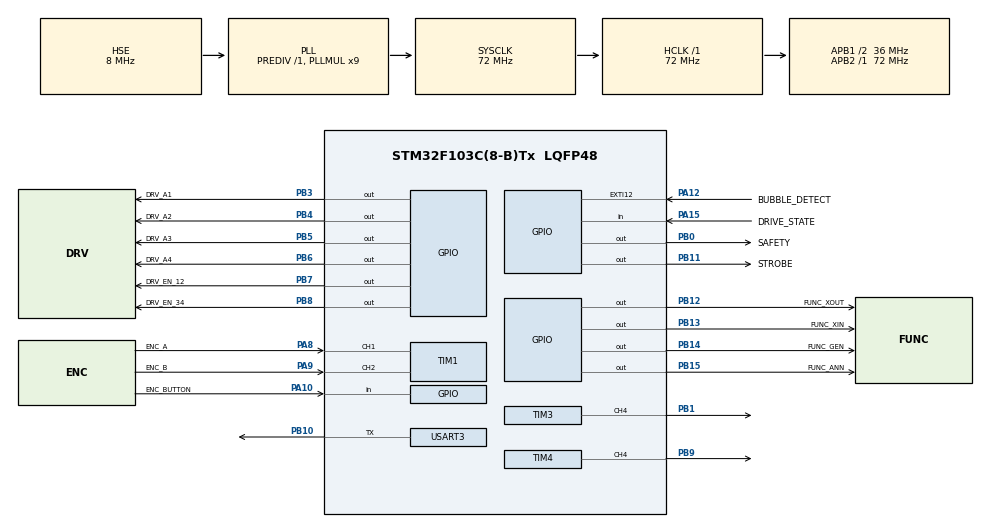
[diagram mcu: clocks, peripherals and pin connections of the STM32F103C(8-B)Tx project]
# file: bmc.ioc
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Dma.Request0=TIM2_UP
Dma.Request1=TIM2_CH1
Dma.Request2=TIM2_CH2/CH4
Dma.TIM2_CH1.1.Direction=DMA_MEMORY_TO_PERIPH
Dma.TIM2_CH1.1.Instance=DMA1_Channel5
Dma.TIM2_CH1.1.MemDataAlignment=DMA_MDATAALIGN_HALFWORD
Dma.TIM2_CH1.1.MemInc=DMA_MINC_DISABLE
Dma.TIM2_CH1.1.Mode=DMA_CIRCULAR
Dma.TIM2_CH1.1.PeriphDataAlignment=DMA_PDATAALIGN_HALFWORD
Dma.TIM2_CH1.1.PeriphInc=DMA_PINC_DISABLE
Dma.TIM2_CH1.1.Priority=DMA_PRIORITY_VERY_HIGH
Dma.TIM2_CH2/CH4.2.Direction=DMA_MEMORY_TO_PERIPH
Dma.TIM2_CH2/CH4.2.Instance=DMA1_Channel7
Dma.TIM2_CH2/CH4.2.MemDataAlignment=DMA_MDATAALIGN_HALFWORD
Dma.TIM2_CH2/CH4.2.MemInc=DMA_MINC_DISABLE
Dma.TIM2_CH2/CH4.2.Mode=DMA_CIRCULAR
Dma.TIM2_CH2/CH4.2.PeriphDataAlignment=DMA_PDATAALIGN_HALFWORD
Dma.TIM2_CH2/CH4.2.PeriphInc=DMA_PINC_DISABLE
Dma.TIM2_CH2/CH4.2.Priority=DMA_PRIORITY_VERY_HIGH
Dma.TIM2_UP.0.Direction=DMA_MEMORY_TO_PERIPH
Dma.TIM2_UP.0.Instance=DMA1_Channel2
Dma.TIM2_UP.0.MemDataAlignment=DMA_MDATAALIGN_HALFWORD
Dma.TIM2_UP.0.MemInc=DMA_MINC_DISABLE
Dma.TIM2_UP.0.Mode=DMA_CIRCULAR
Dma.TIM2_UP.0.PeriphDataAlignment=DMA_PDATAALIGN_HALFWORD
Dma.TIM2_UP.0.PeriphInc=DMA_PINC_DISABLE
Dma.TIM2_UP.0.Priority=DMA_PRIORITY_VERY_HIGH
Mcu.Family=STM32F1
Mcu.Name=STM32F103C(8-B)Tx
Mcu.Package=LQFP48
NVIC.DMA1_Channel2_IRQn=true\:0\:0\:false\:false\:true\:false\:true
NVIC.DMA1_Channel5_IRQn=true\:0\:0\:false\:false\:true\:false\:true
NVIC.DMA1_Channel7_IRQn=true\:0\:0\:false\:false\:true\:false\:true
NVIC.PriorityGroup=NVIC_PRIORITYGROUP_4
PA10.GPIO_Label=ENC_BUTTON
PA10.GPIO_PuPd=GPIO_PULLUP
PA10.Signal=GPIO_Input
PA12.GPIO_Label=BUBBLE_DETECT
PA12.Signal=GPXTI12
PA15.GPIO_Label=DRIVE_STATE
PA15.GPIO_PuPd=GPIO_PULLUP
PA15.Signal=GPIO_Input
PA8.GPIO_Label=ENC_A
PA8.GPIO_PuPd=GPIO_PULLUP
PA8.Signal=S_TIM1_CH1
PA9.GPIO_Label=ENC_B
PA9.GPIO_PuPd=GPIO_PULLUP
PA9.Signal=S_TIM1_CH2
PB0.GPIO_Label=SAFETY
PB0.GPIO_PuPd=GPIO_PULLUP
PB0.GPIO_Speed=GPIO_SPEED_FREQ_HIGH
PB0.PinState=GPIO_PIN_SET
PB0.Signal=GPIO_Output
PB1.Signal=S_TIM3_CH4
PB10.Mode=Half_duplex(single_wire_mode)
PB10.Signal=USART3_TX
PB11.GPIO_Label=STROBE
PB11.GPIO_Speed=GPIO_SPEED_FREQ_HIGH
PB11.Signal=GPIO_Output
PB12.GPIO_Label=FUNC_XOUT
PB12.GPIO_Speed=GPIO_SPEED_FREQ_HIGH
PB12.Signal=GPIO_Output
PB13.GPIO_Label=FUNC_XIN
PB13.GPIO_Speed=GPIO_SPEED_FREQ_HIGH
PB13.Signal=GPIO_Output
PB14.GPIO_Label=FUNC_GEN
PB14.GPIO_Speed=GPIO_SPEED_FREQ_HIGH
PB14.Signal=GPIO_Output
PB15.GPIO_Label=FUNC_ANN
PB15.GPIO_Speed=GPIO_SPEED_FREQ_HIGH
PB15.Signal=GPIO_Output
PB3.GPIO_Label=DRV_A1
PB3.GPIO_Speed=GPIO_SPEED_FREQ_HIGH
PB3.Signal=GPIO_Output
PB4.GPIO_Label=DRV_A2
PB4.GPIO_Speed=GPIO_SPEED_FREQ_HIGH
PB4.Signal=GPIO_Output
PB5.GPIO_Label=DRV_A3
PB5.GPIO_Speed=GPIO_SPEED_FREQ_HIGH
PB5.Signal=GPIO_Output
PB6.GPIO_Label=DRV_A4
PB6.GPIO_Speed=GPIO_SPEED_FREQ_HIGH
PB6.Signal=GPIO_Output
PB7.GPIO_Label=DRV_EN_12
PB7.GPIO_Speed=GPIO_SPEED_FREQ_HIGH
PB7.Signal=GPIO_Output
PB8.GPIO_Label=DRV_EN_34
PB8.GPIO_PuPd=GPIO_NOPULL
PB8.GPIO_Speed=GPIO_SPEED_FREQ_HIGH
PB8.PinState=GPIO_PIN_RESET
PB8.Signal=GPIO_Output
PB9.Signal=S_TIM4_CH4
PD0-OSC_IN.Mode=HSE-External-Oscillator
PD0-OSC_IN.Signal=RCC_OSC_IN
PD1-OSC_OUT.Mode=HSE-External-Oscillator
PD1-OSC_OUT.Signal=RCC_OSC_OUT
ProjectManager.HeapSize=0x200
ProjectManager.StackSize=0x400
ProjectManager.TargetToolchain=Makefile
RCC.AHBFreq_Value=72000000
RCC.APB1CLKDivider=RCC_HCLK_DIV2
RCC.APB1Freq_Value=36000000
RCC.APB1TimFreq_Value=72000000
RCC.APB2Freq_Value=72000000
RCC.APB2TimFreq_Value=72000000
RCC.HCLKFreq_Value=72000000
RCC.PLLMUL=RCC_PLL_MUL9
RCC.PLLSourceVirtual=RCC_PLLSOURCE_HSE
RCC.RTCClockSelection=RCC_RTCCLKSOURCE_LSE
RCC.SYSCLKFreq_VALUE=72000000
RCC.SYSCLKSource=RCC_SYSCLKSOURCE_PLLCLK
RCC.USBFreq_Value=72000000
SH.S_TIM1_CH1.0=TIM1_CH1,Input_Capture1_from_TI1
SH.S_TIM1_CH2.0=TIM1_CH2,Input_Capture2_from_TI2
SH.S_TIM3_CH4.0=TIM3_CH4,PWM Generation4 CH4
SH.S_TIM4_CH4.0=TIM4_CH4,PWM Generation4 CH4
TIM1.Channel-Input_Capture1_from_TI1=TIM_CHANNEL_1
TIM1.Channel-Input_Capture2_from_TI2=TIM_CHANNEL_2
TIM2.Channel-PWM\ Generation1\ No\ Output=TIM_CHANNEL_1
TIM2.Channel-PWM\ Generation2\ No\ Output=TIM_CHANNEL_2
TIM3.AutoReloadPreload=TIM_AUTORELOAD_PRELOAD_ENABLE
TIM3.Channel-PWM\ Generation4\ CH4=TIM_CHANNEL_4
TIM3.OC4Preload_PWM=DISABLE
TIM3.OCFastMode_PWM-PWM\ Generation4\ CH4=TIM_OCFAST_ENABLE
TIM3.Period=999
TIM3.Prescaler=71
TIM3.Pulse-PWM\ Generation4\ CH4=499
TIM4.AutoReloadPreload=TIM_AUTORELOAD_PRELOAD_ENABLE
TIM4.Channel-PWM\ Generation4\ CH4=TIM_CHANNEL_4
TIM4.OC4Preload_PWM=DISABLE
TIM4.OCFastMode_PWM-PWM\ Generation4\ CH4=TIM_OCFAST_ENABLE
TIM4.Period=99
TIM4.Prescaler=71
TIM4.Pulse-PWM\ Generation4\ CH4=49
USART3.Mode=MODE_TX
USART3.VirtualMode=VM_ASYNC
VP_SYS_VS_ND.Mode=No_Debug
VP_TIM2_VS_ClockSourceINT.Mode=Internal
VP_TIM2_VS_no_output1.Mode=PWM Generation1 No Output
VP_TIM2_VS_no_output2.Mode=PWM Generation2 No Output
VP_TIM3_VS_ClockSourceINT.Mode=Internal
VP_TIM4_VS_ClockSourceINT.Mode=Internal
board=custom

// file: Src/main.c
/* USER CODE BEGIN Header */
/**
  ******************************************************************************
  * @file           : main.c
  * @brief          : Main program body
  ******************************************************************************
  ** This notice applies to any and all portions of this file
  * that are not between comment pairs USER CODE BEGIN and
  * USER CODE END. Other portions of this file, whether
  * inserted by the user or by software development tools
  * are owned by their respective copyright owners.
  *
  * COPYRIGHT(c) 2020 STMicroelectronics
  *
  * Redistribution and use in source and binary forms, with or without modification,
  * are permitted provided that the following conditions are met:
  *   1. Redistributions of source code must retain the above copyright notice,
  *      this list of conditions and the following disclaimer.
  *   2. Redistributions in binary form must reproduce the above copyright notice,
  *      this list of conditions and the following disclaimer in the documentation
  *      and/or other materials provided with the distribution.
  *   3. Neither the name of STMicroelectronics nor the names of its contributors
  *      may be used to endorse or promote products derived from this software
  *      without specific prior written permission.
  *
  * THIS SOFTWARE IS PROVIDED BY THE COPYRIGHT HOLDERS AND CONTRIBUTORS "AS IS"
  * AND ANY EXPRESS OR IMPLIED WARRANTIES, INCLUDING, BUT NOT LIMITED TO, THE
  * IMPLIED WARRANTIES OF MERCHANTABILITY AND FITNESS FOR A PARTICULAR PURPOSE ARE
  * DISCLAIMED. IN NO EVENT SHALL THE COPYRIGHT HOLDER OR CONTRIBUTORS BE LIABLE
  * FOR ANY DIRECT, INDIRECT, INCIDENTAL, SPECIAL, EXEMPLARY, OR CONSEQUENTIAL
  * DAMAGES (INCLUDING, BUT NOT LIMITED TO, PROCUREMENT OF SUBSTITUTE GOODS OR
  * SERVICES; LOSS OF USE, DATA, OR PROFITS; OR BUSINESS INTERRUPTION) HOWEVER
  * CAUSED AND ON ANY THEORY OF LIABILITY, WHETHER IN CONTRACT, STRICT LIABILITY,
  * OR TORT (INCLUDING NEGLIGENCE OR OTHERWISE) ARISING IN ANY WAY OUT OF THE USE
  * OF THIS SOFTWARE, EVEN IF ADVISED OF THE POSSIBILITY OF SUCH DAMAGE.
  *
  ******************************************************************************
  */
/* USER CODE END Header */

#include "main.h"

TIM_HandleTypeDef htim1;
TIM_HandleTypeDef htim2;
TIM_HandleTypeDef htim3;
TIM_HandleTypeDef htim4;
DMA_HandleTypeDef hdma_tim2_up;
DMA_HandleTypeDef hdma_tim2_ch1;
DMA_HandleTypeDef hdma_tim2_ch2_ch4;

UART_HandleTypeDef huart3;

void SystemClock_Config(void);
static void MX_GPIO_Init(void);
static void MX_DMA_Init(void);
static void MX_TIM2_Init(void);
static void MX_TIM3_Init(void);
static void MX_TIM4_Init(void);
static void MX_TIM1_Init(void);
static void MX_USART3_UART_Init(void);

/* USER CODE BEGIN 0 */
int app_main();
/* USER CODE END 0 */

int main(void)
{

  /* MCU Configuration--------------------------------------------------------*/

  /* Reset of all peripherals, Initializes the Flash interface and the Systick. */
  HAL_Init();

  /* Configure the system clock */
  SystemClock_Config();

  /* Initialize all configured peripherals */
  MX_GPIO_Init();
  MX_DMA_Init();
  MX_TIM2_Init();
  MX_TIM3_Init();
  MX_TIM4_Init();
  MX_TIM1_Init();
  MX_USART3_UART_Init();
  /* USER CODE BEGIN 2 */
  app_main();
  /* USER CODE END 2 */

  /* Infinite loop */
  while (1)
  {

  }
}

void SystemClock_Config(void)
{
  RCC_OscInitTypeDef RCC_OscInitStruct = {0};
  RCC_ClkInitTypeDef RCC_ClkInitStruct = {0};

  /** Initializes the CPU, AHB and APB busses clocks
  */
  RCC_OscInitStruct.OscillatorType = RCC_OSCILLATORTYPE_HSE;
  RCC_OscInitStruct.HSEState = RCC_HSE_ON;
  RCC_OscInitStruct.HSEPredivValue = RCC_HSE_PREDIV_DIV1;
  RCC_OscInitStruct.HSIState = RCC_HSI_ON;
  RCC_OscInitStruct.PLL.PLLState = RCC_PLL_ON;
  RCC_OscInitStruct.PLL.PLLSource = RCC_PLLSOURCE_HSE;
  RCC_OscInitStruct.PLL.PLLMUL = RCC_PLL_MUL9;
  if (HAL_RCC_OscConfig(&RCC_OscInitStruct) != HAL_OK)
  {
    Error_Handler();
  }
  /** Initializes the CPU, AHB and APB busses clocks
  */
  RCC_ClkInitStruct.ClockType = RCC_CLOCKTYPE_HCLK|RCC_CLOCKTYPE_SYSCLK
                              |RCC_CLOCKTYPE_PCLK1|RCC_CLOCKTYPE_PCLK2;
  RCC_ClkInitStruct.SYSCLKSource = RCC_SYSCLKSOURCE_PLLCLK;
  RCC_ClkInitStruct.AHBCLKDivider = RCC_SYSCLK_DIV1;
  RCC_ClkInitStruct.APB1CLKDivider = RCC_HCLK_DIV2;
  RCC_ClkInitStruct.APB2CLKDivider = RCC_HCLK_DIV1;

  if (HAL_RCC_ClockConfig(&RCC_ClkInitStruct, FLASH_LATENCY_2) != HAL_OK)
  {
    Error_Handler();
  }
}

static void MX_TIM1_Init(void)
{

  TIM_MasterConfigTypeDef sMasterConfig = {0};
  TIM_IC_InitTypeDef sConfigIC = {0};

  htim1.Instance = TIM1;
  htim1.Init.Prescaler = 0;
  htim1.Init.CounterMode = TIM_COUNTERMODE_UP;
  htim1.Init.Period = 0;
  htim1.Init.ClockDivision = TIM_CLOCKDIVISION_DIV1;
  htim1.Init.RepetitionCounter = 0;
  htim1.Init.AutoReloadPreload = TIM_AUTORELOAD_PRELOAD_DISABLE;
  if (HAL_TIM_IC_Init(&htim1) != HAL_OK)
  {
    Error_Handler();
  }
  sMasterConfig.MasterOutputTrigger = TIM_TRGO_RESET;
  sMasterConfig.MasterSlaveMode = TIM_MASTERSLAVEMODE_DISABLE;
  if (HAL_TIMEx_MasterConfigSynchronization(&htim1, &sMasterConfig) != HAL_OK)
  {
    Error_Handler();
  }
  sConfigIC.ICPolarity = TIM_INPUTCHANNELPOLARITY_RISING;
  sConfigIC.ICSelection = TIM_ICSELECTION_DIRECTTI;
  sConfigIC.ICPrescaler = TIM_ICPSC_DIV1;
  sConfigIC.ICFilter = 0;
  if (HAL_TIM_IC_ConfigChannel(&htim1, &sConfigIC, TIM_CHANNEL_1) != HAL_OK)
  {
    Error_Handler();
  }
  if (HAL_TIM_IC_ConfigChannel(&htim1, &sConfigIC, TIM_CHANNEL_2) != HAL_OK)
  {
    Error_Handler();
  }

}

static void MX_TIM2_Init(void)
{

  TIM_ClockConfigTypeDef sClockSourceConfig = {0};
  TIM_MasterConfigTypeDef sMasterConfig = {0};
  TIM_OC_InitTypeDef sConfigOC = {0};

  htim2.Instance = TIM2;
  htim2.Init.Prescaler = 0;
  htim2.Init.CounterMode = TIM_COUNTERMODE_UP;
  htim2.Init.Period = 0;
  htim2.Init.ClockDivision = TIM_CLOCKDIVISION_DIV1;
  htim2.Init.AutoReloadPreload = TIM_AUTORELOAD_PRELOAD_DISABLE;
  if (HAL_TIM_Base_Init(&htim2) != HAL_OK)
  {
    Error_Handler();
  }
  sClockSourceConfig.ClockSource = TIM_CLOCKSOURCE_INTERNAL;
  if (HAL_TIM_ConfigClockSource(&htim2, &sClockSourceConfig) != HAL_OK)
  {
    Error_Handler();
  }
  if (HAL_TIM_PWM_Init(&htim2) != HAL_OK)
  {
    Error_Handler();
  }
  sMasterConfig.MasterOutputTrigger = TIM_TRGO_RESET;
  sMasterConfig.MasterSlaveMode = TIM_MASTERSLAVEMODE_DISABLE;
  if (HAL_TIMEx_MasterConfigSynchronization(&htim2, &sMasterConfig) != HAL_OK)
  {
    Error_Handler();
  }
  sConfigOC.OCMode = TIM_OCMODE_PWM1;
  sConfigOC.Pulse = 0;
  sConfigOC.OCPolarity = TIM_OCPOLARITY_HIGH;
  sConfigOC.OCFastMode = TIM_OCFAST_DISABLE;
  if (HAL_TIM_PWM_ConfigChannel(&htim2, &sConfigOC, TIM_CHANNEL_1) != HAL_OK)
  {
    Error_Handler();
  }
  if (HAL_TIM_PWM_ConfigChannel(&htim2, &sConfigOC, TIM_CHANNEL_2) != HAL_OK)
  {
    Error_Handler();
  }

}

static void MX_TIM3_Init(void)
{

  TIM_ClockConfigTypeDef sClockSourceConfig = {0};
  TIM_MasterConfigTypeDef sMasterConfig = {0};
  TIM_OC_InitTypeDef sConfigOC = {0};

  htim3.Instance = TIM3;
  htim3.Init.Prescaler = 71;
  htim3.Init.CounterMode = TIM_COUNTERMODE_UP;
  htim3.Init.Period = 999;
  htim3.Init.ClockDivision = TIM_CLOCKDIVISION_DIV1;
  htim3.Init.AutoReloadPreload = TIM_AUTORELOAD_PRELOAD_ENABLE;
  if (HAL_TIM_Base_Init(&htim3) != HAL_OK)
  {
    Error_Handler();
  }
  sClockSourceConfig.ClockSource = TIM_CLOCKSOURCE_INTERNAL;
  if (HAL_TIM_ConfigClockSource(&htim3, &sClockSourceConfig) != HAL_OK)
  {
    Error_Handler();
  }
  if (HAL_TIM_PWM_Init(&htim3) != HAL_OK)
  {
    Error_Handler();
  }
  sMasterConfig.MasterOutputTrigger = TIM_TRGO_RESET;
  sMasterConfig.MasterSlaveMode = TIM_MASTERSLAVEMODE_DISABLE;
  if (HAL_TIMEx_MasterConfigSynchronization(&htim3, &sMasterConfig) != HAL_OK)
  {
    Error_Handler();
  }
  sConfigOC.OCMode = TIM_OCMODE_PWM1;
  sConfigOC.Pulse = 499;
  sConfigOC.OCPolarity = TIM_OCPOLARITY_HIGH;
  sConfigOC.OCFastMode = TIM_OCFAST_ENABLE;
  if (HAL_TIM_PWM_ConfigChannel(&htim3, &sConfigOC, TIM_CHANNEL_4) != HAL_OK)
  {
    Error_Handler();
  }
  __HAL_TIM_DISABLE_OCxPRELOAD(&htim3, TIM_CHANNEL_4);
  HAL_TIM_MspPostInit(&htim3);

}

static void MX_TIM4_Init(void)
{

  TIM_ClockConfigTypeDef sClockSourceConfig = {0};
  TIM_MasterConfigTypeDef sMasterConfig = {0};
  TIM_OC_InitTypeDef sConfigOC = {0};

  htim4.Instance = TIM4;
  htim4.Init.Prescaler = 71;
  htim4.Init.CounterMode = TIM_COUNTERMODE_UP;
  htim4.Init.Period = 99;
  htim4.Init.ClockDivision = TIM_CLOCKDIVISION_DIV1;
  htim4.Init.AutoReloadPreload = TIM_AUTORELOAD_PRELOAD_ENABLE;
  if (HAL_TIM_Base_Init(&htim4) != HAL_OK)
  {
    Error_Handler();
  }
  sClockSourceConfig.ClockSource = TIM_CLOCKSOURCE_INTERNAL;
  if (HAL_TIM_ConfigClockSource(&htim4, &sClockSourceConfig) != HAL_OK)
  {
    Error_Handler();
  }
  if (HAL_TIM_PWM_Init(&htim4) != HAL_OK)
  {
    Error_Handler();
  }
  sMasterConfig.MasterOutputTrigger = TIM_TRGO_RESET;
  sMasterConfig.MasterSlaveMode = TIM_MASTERSLAVEMODE_DISABLE;
  if (HAL_TIMEx_MasterConfigSynchronization(&htim4, &sMasterConfig) != HAL_OK)
  {
    Error_Handler();
  }
  sConfigOC.OCMode = TIM_OCMODE_PWM1;
  sConfigOC.Pulse = 49;
  sConfigOC.OCPolarity = TIM_OCPOLARITY_HIGH;
  sConfigOC.OCFastMode = TIM_OCFAST_ENABLE;
  if (HAL_TIM_PWM_ConfigChannel(&htim4, &sConfigOC, TIM_CHANNEL_4) != HAL_OK)
  {
    Error_Handler();
  }
  __HAL_TIM_DISABLE_OCxPRELOAD(&htim4, TIM_CHANNEL_4);
  HAL_TIM_MspPostInit(&htim4);

}

static void MX_USART3_UART_Init(void)
{

  huart3.Instance = USART3;
  huart3.Init.BaudRate = 115200;
  huart3.Init.WordLength = UART_WORDLENGTH_8B;
  huart3.Init.StopBits = UART_STOPBITS_1;
  huart3.Init.Parity = UART_PARITY_NONE;
  huart3.Init.Mode = UART_MODE_TX;
  huart3.Init.HwFlowCtl = UART_HWCONTROL_NONE;
  huart3.Init.OverSampling = UART_OVERSAMPLING_16;
  if (HAL_HalfDuplex_Init(&huart3) != HAL_OK)
  {
    Error_Handler();
  }

}

static void MX_DMA_Init(void)
{

  /* DMA controller clock enable */
  __HAL_RCC_DMA1_CLK_ENABLE();

  /* DMA interrupt init */
  /* DMA1_Channel2_IRQn interrupt configuration */
  HAL_NVIC_SetPriority(DMA1_Channel2_IRQn, 0, 0);
  HAL_NVIC_EnableIRQ(DMA1_Channel2_IRQn);
  /* DMA1_Channel5_IRQn interrupt configuration */
  HAL_NVIC_SetPriority(DMA1_Channel5_IRQn, 0, 0);
  HAL_NVIC_EnableIRQ(DMA1_Channel5_IRQn);
  /* DMA1_Channel7_IRQn interrupt configuration */
  HAL_NVIC_SetPriority(DMA1_Channel7_IRQn, 0, 0);
  HAL_NVIC_EnableIRQ(DMA1_Channel7_IRQn);

}

static void MX_GPIO_Init(void)
{
  GPIO_InitTypeDef GPIO_InitStruct = {0};

  /* GPIO Ports Clock Enable */
  __HAL_RCC_GPIOC_CLK_ENABLE();
  __HAL_RCC_GPIOD_CLK_ENABLE();
  __HAL_RCC_GPIOA_CLK_ENABLE();
  __HAL_RCC_GPIOB_CLK_ENABLE();

  /*Configure GPIO pin Output Level */
  HAL_GPIO_WritePin(GPIOC, LCD_DI_Pin|LCD_CS2_Pin|LCD_CS1_Pin, GPIO_PIN_RESET);

  /*Configure GPIO pin Output Level */
  HAL_GPIO_WritePin(GPIOA, LCD_D0_Pin|LCD_D1_Pin|LCD_D2_Pin|LCD_D3_Pin
                          |LCD_D4_Pin|LCD_D5_Pin|LCD_D6_Pin|LCD_D7_Pin, GPIO_PIN_RESET);

  /*Configure GPIO pin Output Level */
  HAL_GPIO_WritePin(SAFETY_GPIO_Port, SAFETY_Pin, GPIO_PIN_SET);

  /*Configure GPIO pin Output Level */
  HAL_GPIO_WritePin(GPIOB, LCD_E_Pin|STROBE_Pin|FUNC_XOUT_Pin|FUNC_XIN_Pin
                          |FUNC_GEN_Pin|FUNC_ANN_Pin|DRV_A1_Pin|DRV_A2_Pin
                          |DRV_A3_Pin|DRV_A4_Pin|DRV_EN_12_Pin|DRV_EN_34_Pin, GPIO_PIN_RESET);

  /*Configure GPIO pins : LCD_DI_Pin LCD_CS2_Pin LCD_CS1_Pin */
  GPIO_InitStruct.Pin = LCD_DI_Pin|LCD_CS2_Pin|LCD_CS1_Pin;
  GPIO_InitStruct.Mode = GPIO_MODE_OUTPUT_PP;
  GPIO_InitStruct.Pull = GPIO_NOPULL;
  GPIO_InitStruct.Speed = GPIO_SPEED_FREQ_HIGH;
  HAL_GPIO_Init(GPIOC, &GPIO_InitStruct);

  /*Configure GPIO pins : LCD_D0_Pin LCD_D1_Pin LCD_D2_Pin LCD_D3_Pin
                           LCD_D4_Pin LCD_D5_Pin LCD_D6_Pin LCD_D7_Pin */
  GPIO_InitStruct.Pin = LCD_D0_Pin|LCD_D1_Pin|LCD_D2_Pin|LCD_D3_Pin
                          |LCD_D4_Pin|LCD_D5_Pin|LCD_D6_Pin|LCD_D7_Pin;
  GPIO_InitStruct.Mode = GPIO_MODE_OUTPUT_PP;
  GPIO_InitStruct.Pull = GPIO_NOPULL;
  GPIO_InitStruct.Speed = GPIO_SPEED_FREQ_HIGH;
  HAL_GPIO_Init(GPIOA, &GPIO_InitStruct);

  /*Configure GPIO pin : SAFETY_Pin */
  GPIO_InitStruct.Pin = SAFETY_Pin;
  GPIO_InitStruct.Mode = GPIO_MODE_OUTPUT_PP;
  GPIO_InitStruct.Pull = GPIO_PULLUP;
  GPIO_InitStruct.Speed = GPIO_SPEED_FREQ_HIGH;
  HAL_GPIO_Init(SAFETY_GPIO_Port, &GPIO_InitStruct);

  /*Configure GPIO pins : LCD_E_Pin STROBE_Pin FUNC_XOUT_Pin FUNC_XIN_Pin
                           FUNC_GEN_Pin FUNC_ANN_Pin DRV_A1_Pin DRV_A2_Pin
                           DRV_A3_Pin DRV_A4_Pin DRV_EN_12_Pin DRV_EN_34_Pin */
  GPIO_InitStruct.Pin = LCD_E_Pin|STROBE_Pin|FUNC_XOUT_Pin|FUNC_XIN_Pin
                          |FUNC_GEN_Pin|FUNC_ANN_Pin|DRV_A1_Pin|DRV_A2_Pin
                          |DRV_A3_Pin|DRV_A4_Pin|DRV_EN_12_Pin|DRV_EN_34_Pin;
  GPIO_InitStruct.Mode = GPIO_MODE_OUTPUT_PP;
  GPIO_InitStruct.Pull = GPIO_NOPULL;
  GPIO_InitStruct.Speed = GPIO_SPEED_FREQ_HIGH;
  HAL_GPIO_Init(GPIOB, &GPIO_InitStruct);

  /*Configure GPIO pins : ENC_BUTTON_Pin DRIVE_STATE_Pin */
  GPIO_InitStruct.Pin = ENC_BUTTON_Pin|DRIVE_STATE_Pin;
  GPIO_InitStruct.Mode = GPIO_MODE_INPUT;
  GPIO_InitStruct.Pull = GPIO_PULLUP;
  HAL_GPIO_Init(GPIOA, &GPIO_InitStruct);

  /*Configure GPIO pin : BUBBLE_DETECT_Pin */
  GPIO_InitStruct.Pin = BUBBLE_DETECT_Pin;
  GPIO_InitStruct.Mode = GPIO_MODE_IT_RISING;
  GPIO_InitStruct.Pull = GPIO_NOPULL;
  HAL_GPIO_Init(BUBBLE_DETECT_GPIO_Port, &GPIO_InitStruct);

}

void Error_Handler(void)
{
}

/************************ (C) COPYRIGHT STMicroelectronics *****END OF FILE****/
